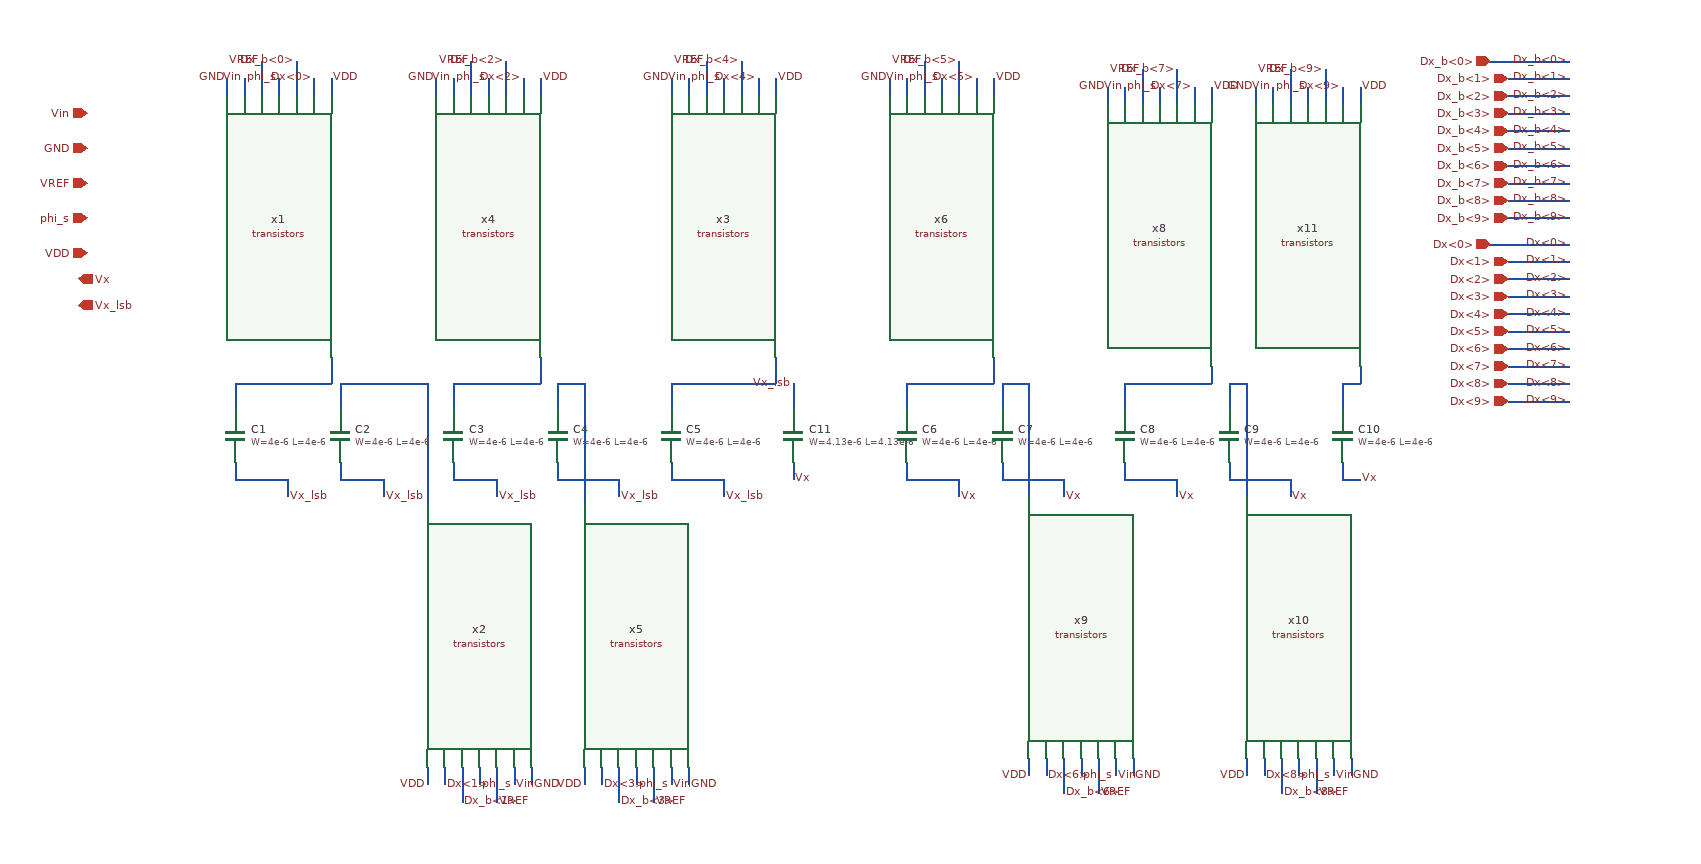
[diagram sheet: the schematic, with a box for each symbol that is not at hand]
v {xschem version=3.4.8RC file_version=1.3}
G {}
K {}
V {}
S {}
F {}
E {}
N -220 -110 -220 -90 {lab=Vx_lsb}
N -100 -110 -100 -90 {lab=Vx_lsb}
N 30 -110 30 -90 {lab=Vx_lsb}
N 150 -110 150 -90 {lab=Vx_lsb}
N 280 -110 280 -90 {lab=Vx_lsb}
N 920 -110 920 -90 {lab=Vx}
N 800 -110 800 -90 {lab=Vx}
N 660 -110 660 -90 {lab=Vx}
N 550 -110 550 -90 {lab=Vx}
N 420 -110 420 -90 {lab=Vx}
N -100 -200 -100 -170 {lab=#net1}
N -220 -200 -220 -170 {lab=#net2}
N 30 -200 30 -170 {lab=#net3}
N 150 -200 150 -170 {lab=#net4}
N 280 -200 280 -170 {lab=#net5}
N 550 -200 550 -170 {lab=#net6}
N 660 -200 660 -170 {lab=#net7}
N 800 -200 800 -170 {lab=#net8}
N 920 -200 920 -170 {lab=#net9}
N 1050 -110 1050 -90 {lab=Vx}
N -110 -230 -110 -200 {lab=#net2}
N -0 -200 0 -60 {lab=#net1}
N 180 -200 180 -70 {lab=#net4}
N 180 -70 180 -60 {lab=#net4}
N 130 -230 130 -200 {lab=#net3}
N 400 -230 400 -200 {lab=#net5}
N 650 -230 650 -200 {lab=#net6}
N 940 -200 940 -70 {lab=#net9}
N 900 -220 900 -200 {lab=#net8}
N 690 -200 690 -70 {lab=#net7}
N -230 -550 -230 -530 {lab=GND}
N -210 -550 -210 -530 {lab=Vin}
N -190 -550 -190 -530 {lab=VREF}
N -170 -550 -170 -530 {lab=phi_s}
N -150 -550 -150 -530 {lab=Dx_b<0>}
N -130 -550 -130 -530 {lab=Dx<0>}
N -110 -550 -110 -530 {lab=VDD}
N -190 -570 -190 -550 {lab=VREF}
N -150 -570 -150 -550 {lab=Dx_b<0>}
N 10 -550 10 -530 {lab=GND}
N 30 -550 30 -530 {lab=Vin}
N 50 -550 50 -530 {lab=VREF}
N 70 -550 70 -530 {lab=phi_s}
N 90 -550 90 -530 {lab=Dx_b<2>}
N 110 -550 110 -530 {lab=Dx<2>}
N 130 -550 130 -530 {lab=VDD}
N 50 -570 50 -550 {lab=VREF}
N 90 -570 90 -550 {lab=Dx_b<2>}
N 280 -550 280 -530 {lab=GND}
N 300 -550 300 -530 {lab=Vin}
N 320 -550 320 -530 {lab=VREF}
N 340 -550 340 -530 {lab=phi_s}
N 360 -550 360 -530 {lab=Dx_b<4>}
N 380 -550 380 -530 {lab=Dx<4>}
N 400 -550 400 -530 {lab=VDD}
N 320 -570 320 -550 {lab=VREF}
N 360 -570 360 -550 {lab=Dx_b<4>}
N 530 -550 530 -530 {lab=GND}
N 550 -550 550 -530 {lab=Vin}
N 570 -550 570 -530 {lab=VREF}
N 590 -550 590 -530 {lab=phi_s}
N 610 -550 610 -530 {lab=Dx_b<5>}
N 630 -550 630 -530 {lab=Dx<5>}
N 650 -550 650 -530 {lab=VDD}
N 570 -570 570 -550 {lab=VREF}
N 610 -570 610 -550 {lab=Dx_b<5>}
N 780 -540 780 -520 {lab=GND}
N 800 -540 800 -520 {lab=Vin}
N 820 -540 820 -520 {lab=VREF}
N 840 -540 840 -520 {lab=phi_s}
N 860 -540 860 -520 {lab=Dx_b<7>}
N 880 -540 880 -520 {lab=Dx<7>}
N 900 -540 900 -520 {lab=VDD}
N 820 -560 820 -540 {lab=VREF}
N 860 -560 860 -540 {lab=Dx_b<7>}
N 120 240 120 260 {lab=GND}
N 100 240 100 260 {lab=Vin}
N 80 240 80 260 {lab=VREF}
N 60 240 60 260 {lab=phi_s}
N 40 240 40 260 {lab=Dx_b<1>}
N 20 240 20 260 {lab=Dx<1>}
N 0 240 0 260 {lab=VDD}
N 80 260 80 280 {lab=VREF}
N 40 260 40 280 {lab=Dx_b<1>}
N 300 240 300 260 {lab=GND}
N 280 240 280 260 {lab=Vin}
N 260 240 260 260 {lab=VREF}
N 240 240 240 260 {lab=phi_s}
N 220 240 220 260 {lab=Dx_b<3>}
N 200 240 200 260 {lab=Dx<3>}
N 180 240 180 260 {lab=VDD}
N 260 260 260 280 {lab=VREF}
N 220 260 220 280 {lab=Dx_b<3>}
N 810 230 810 250 {lab=GND}
N 790 230 790 250 {lab=Vin}
N 770 230 770 250 {lab=VREF}
N 750 230 750 250 {lab=phi_s}
N 730 230 730 250 {lab=Dx_b<6>}
N 710 230 710 250 {lab=Dx<6>}
N 690 230 690 250 {lab=VDD}
N 770 250 770 270 {lab=VREF}
N 730 250 730 270 {lab=Dx_b<6>}
N 1060 230 1060 250 {lab=GND}
N 1040 230 1040 250 {lab=Vin}
N 1020 230 1020 250 {lab=VREF}
N 1000 230 1000 250 {lab=phi_s}
N 980 230 980 250 {lab=Dx_b<8>}
N 960 230 960 250 {lab=Dx<8>}
N 940 230 940 250 {lab=VDD}
N 1020 250 1020 270 {lab=VREF}
N 980 250 980 270 {lab=Dx_b<8>}
N 990 -90 990 -70 {lab=Vx}
N 860 -90 860 -70 {lab=Vx}
N 730 -90 730 -80 {lab=Vx}
N 1050 -90 1070 -90 {lab=Vx}
N 730 -80 730 -70 {lab=Vx}
N 610 -90 610 -70 {lab=Vx}
N 340 -90 340 -70 {lab=Vx_lsb}
N 220 -90 220 -70 {lab=Vx_lsb}
N -50 -90 -50 -70 {lab=Vx_lsb}
N 80 -90 80 -70 {lab=Vx_lsb}
N -160 -90 -160 -70 {lab=Vx_lsb}
N -220 -90 -160 -90 {lab=Vx_lsb}
N -100 -90 -50 -90 {lab=Vx_lsb}
N 30 -90 80 -90 {lab=Vx_lsb}
N 150 -90 220 -90 {lab=Vx_lsb}
N 280 -90 340 -90 {lab=Vx_lsb}
N 920 -90 990 -90 {lab=Vx}
N 800 -90 860 -90 {lab=Vx}
N 660 -90 730 -90 {lab=Vx}
N 550 -90 610 -90 {lab=Vx}
N 1220 -570 1310 -570 {lab=Dx_b<0>}
N 1240 -550 1310 -550 {lab=Dx_b<1>}
N 1240 -530 1310 -530 {lab=Dx_b<2>}
N 1240 -510 1310 -510 {lab=Dx_b<3>}
N 1240 -490 1310 -490 {lab=Dx_b<4>}
N 1240 -470 1310 -470 {lab=Dx_b<5>}
N 1240 -450 1310 -450 {lab=Dx_b<6>}
N 1240 -430 1310 -430 {lab=Dx_b<7>}
N 1240 -410 1310 -410 {lab=Dx_b<8>}
N 1240 -390 1310 -390 {lab=Dx_b<9>}
N 1220 -360 1310 -360 {lab=Dx<0>}
N 1240 -340 1310 -340 {lab=Dx<1>}
N 1240 -320 1310 -320 {lab=Dx<2>}
N 1240 -300 1310 -300 {lab=Dx<3>}
N 1240 -280 1310 -280 {lab=Dx<4>}
N 1240 -260 1310 -260 {lab=Dx<5>}
N 1240 -240 1310 -240 {lab=Dx<6>}
N 1240 -220 1310 -220 {lab=Dx<7>}
N 1240 -200 1310 -200 {lab=Dx<8>}
N 1240 -180 1310 -180 {lab=Dx<9>}
N -100 -200 0 -200 {lab=#net1}
N -220 -200 -110 -200 {lab=#net2}
N 30 -200 130 -200 {lab=#net3}
N 150 -200 180 -200 {lab=#net4}
N 280 -200 400 -200 {lab=#net5}
N 550 -200 650 -200 {lab=#net6}
N 660 -200 690 -200 {lab=#net7}
N 800 -200 900 -200 {lab=#net8}
N 920 -200 940 -200 {lab=#net9}
N 1070 -220 1070 -200 {lab=#net10}
N 1050 -200 1070 -200 {lab=#net10}
N 1050 -200 1050 -170 {lab=#net10}
N 950 -540 950 -520 {lab=GND}
N 970 -540 970 -520 {lab=Vin}
N 990 -540 990 -520 {lab=VREF}
N 1010 -540 1010 -520 {lab=phi_s}
N 1030 -540 1030 -520 {lab=Dx_b<9>}
N 1050 -540 1050 -520 {lab=Dx<9>}
N 1070 -540 1070 -520 {lab=VDD}
N 990 -560 990 -540 {lab=VREF}
N 1030 -560 1030 -540 {lab=Dx_b<9>}
N 420 -200 420 -170 {lab=Vx_lsb}
C {symbols/cap_mim_2f0fF.sym} -220 -140 0 0 {name=C1
W=4e-6
L=4e-6
model=cap_mim_2f0fF
spiceprefix=X
m=1}
C {symbols/cap_mim_2f0fF.sym} -100 -140 0 0 {name=C2
W=4e-6
L=4e-6
model=cap_mim_2f0fF
spiceprefix=X
m=1}
C {symbols/cap_mim_2f0fF.sym} 30 -140 0 0 {name=C3
W=4e-6
L=4e-6
model=cap_mim_2f0fF
spiceprefix=X
m=2}
C {symbols/cap_mim_2f0fF.sym} 150 -140 0 0 {name=C4
W=4e-6
L=4e-6
model=cap_mim_2f0fF
spiceprefix=X
m=4}
C {symbols/cap_mim_2f0fF.sym} 280 -140 0 0 {name=C5
W=4e-6
L=4e-6
model=cap_mim_2f0fF
spiceprefix=X
m=8}
C {symbols/cap_mim_2f0fF.sym} 550 -140 0 0 {name=C6
W=4e-6
L=4e-6
model=cap_mim_2f0fF
spiceprefix=X
m=1}
C {symbols/cap_mim_2f0fF.sym} 660 -140 0 0 {name=C7
W=4e-6
L=4e-6
model=cap_mim_2f0fF
spiceprefix=X
m=1}
C {symbols/cap_mim_2f0fF.sym} 800 -140 0 0 {name=C8
W=4e-6
L=4e-6
model=cap_mim_2f0fF
spiceprefix=X
m=2}
C {symbols/cap_mim_2f0fF.sym} 920 -140 0 0 {name=C9
W=4e-6
L=4e-6
model=cap_mim_2f0fF
spiceprefix=X
m=4}
C {symbols/cap_mim_2f0fF.sym} 1050 -140 0 0 {name=C10
W=4e-6
L=4e-6
model=cap_mim_2f0fF
spiceprefix=X
m=8}
C {symbols/cap_mim_2f0fF.sym} 420 -140 0 0 {name=C11
W=4.13e-6
L=4.13e-6
model=cap_mim_2f0fF
spiceprefix=X
m=1}
C {lab_wire.sym} 990 -70 2 0 {name=p10 sig_type=std_logic lab=Vx}
C {cdac/transistors.sym} -170 -380 1 0 {name=x1}
C {cdac/transistors.sym} 60 90 3 0 {name=x2}
C {cdac/transistors.sym} 340 -380 1 0 {name=x3}
C {cdac/transistors.sym} 70 -380 1 0 {name=x4}
C {cdac/transistors.sym} 240 90 3 0 {name=x5}
C {cdac/transistors.sym} 590 -380 1 0 {name=x6}
C {cdac/transistors.sym} 840 -370 1 0 {name=x8}
C {cdac/transistors.sym} 750 80 3 0 {name=x9}
C {cdac/transistors.sym} 1000 80 3 0 {name=x10}
C {ipin.sym} -390 -510 0 0 {name=p1 lab=Vin}
C {ipin.sym} -390 -470 0 0 {name=p2 lab=GND}
C {ipin.sym} -390 -430 0 0 {name=p3 lab=VREF}
C {opin.sym} -400 -320 0 0 {name=p4 lab=Vx}
C {ipin.sym} -390 -390 0 0 {name=p5 lab=phi_s}
C {ipin.sym} -390 -350 0 0 {name=p6 lab=VDD}
C {ipin.sym} 1220 -570 0 0 {name=p7 lab=Dx_b<0>}
C {ipin.sym} 1220 -360 0 0 {name=p8 lab=Dx<0>}
C {lab_wire.sym} -230 -550 0 0 {name=p9 sig_type=std_logic lab=GND}
C {lab_wire.sym} -210 -550 0 0 {name=p11 sig_type=std_logic lab=Vin}
C {lab_wire.sym} -110 -550 2 0 {name=p12 sig_type=std_logic lab=VDD}
C {lab_wire.sym} -190 -570 0 0 {name=p13 sig_type=std_logic lab=VREF}
C {lab_wire.sym} -170 -550 0 0 {name=p14 sig_type=std_logic lab=phi_s}
C {lab_wire.sym} -150 -570 0 0 {name=p15 sig_type=std_logic lab=Dx_b<0>}
C {lab_wire.sym} -130 -550 0 0 {name=p16 sig_type=std_logic lab=Dx<0>}
C {lab_wire.sym} 10 -550 0 0 {name=p17 sig_type=std_logic lab=GND}
C {lab_wire.sym} 30 -550 0 0 {name=p18 sig_type=std_logic lab=Vin}
C {lab_wire.sym} 130 -550 2 0 {name=p19 sig_type=std_logic lab=VDD}
C {lab_wire.sym} 50 -570 0 0 {name=p20 sig_type=std_logic lab=VREF}
C {lab_wire.sym} 70 -550 0 0 {name=p21 sig_type=std_logic lab=phi_s}
C {lab_wire.sym} 90 -570 0 0 {name=p22 sig_type=std_logic lab=Dx_b<2>}
C {lab_wire.sym} 110 -550 0 0 {name=p23 sig_type=std_logic lab=Dx<2>}
C {lab_wire.sym} 280 -550 0 0 {name=p24 sig_type=std_logic lab=GND}
C {lab_wire.sym} 300 -550 0 0 {name=p25 sig_type=std_logic lab=Vin}
C {lab_wire.sym} 400 -550 2 0 {name=p26 sig_type=std_logic lab=VDD}
C {lab_wire.sym} 320 -570 0 0 {name=p27 sig_type=std_logic lab=VREF}
C {lab_wire.sym} 340 -550 0 0 {name=p28 sig_type=std_logic lab=phi_s}
C {lab_wire.sym} 360 -570 0 0 {name=p29 sig_type=std_logic lab=Dx_b<4>}
C {lab_wire.sym} 380 -550 0 0 {name=p30 sig_type=std_logic lab=Dx<4>}
C {lab_wire.sym} 530 -550 0 0 {name=p31 sig_type=std_logic lab=GND}
C {lab_wire.sym} 550 -550 0 0 {name=p32 sig_type=std_logic lab=Vin}
C {lab_wire.sym} 650 -550 2 0 {name=p33 sig_type=std_logic lab=VDD}
C {lab_wire.sym} 570 -570 0 0 {name=p34 sig_type=std_logic lab=VREF}
C {lab_wire.sym} 590 -550 0 0 {name=p35 sig_type=std_logic lab=phi_s}
C {lab_wire.sym} 610 -570 0 0 {name=p36 sig_type=std_logic lab=Dx_b<5>}
C {lab_wire.sym} 630 -550 0 0 {name=p37 sig_type=std_logic lab=Dx<5>}
C {lab_wire.sym} 780 -540 0 0 {name=p38 sig_type=std_logic lab=GND}
C {lab_wire.sym} 800 -540 0 0 {name=p39 sig_type=std_logic lab=Vin}
C {lab_wire.sym} 900 -540 2 0 {name=p40 sig_type=std_logic lab=VDD}
C {lab_wire.sym} 820 -560 0 0 {name=p41 sig_type=std_logic lab=VREF}
C {lab_wire.sym} 840 -540 0 0 {name=p42 sig_type=std_logic lab=phi_s}
C {lab_wire.sym} 860 -560 0 0 {name=p43 sig_type=std_logic lab=Dx_b<7>}
C {lab_wire.sym} 880 -540 0 0 {name=p44 sig_type=std_logic lab=Dx<7>}
C {lab_wire.sym} 120 260 2 0 {name=p45 sig_type=std_logic lab=GND}
C {lab_wire.sym} 100 260 2 0 {name=p46 sig_type=std_logic lab=Vin}
C {lab_wire.sym} 0 260 0 0 {name=p47 sig_type=std_logic lab=VDD}
C {lab_wire.sym} 80 280 2 0 {name=p48 sig_type=std_logic lab=VREF}
C {lab_wire.sym} 60 260 2 0 {name=p49 sig_type=std_logic lab=phi_s}
C {lab_wire.sym} 40 280 2 0 {name=p50 sig_type=std_logic lab=Dx_b<1>}
C {lab_wire.sym} 20 260 2 0 {name=p51 sig_type=std_logic lab=Dx<1>}
C {lab_wire.sym} 300 260 2 0 {name=p52 sig_type=std_logic lab=GND}
C {lab_wire.sym} 280 260 2 0 {name=p53 sig_type=std_logic lab=Vin}
C {lab_wire.sym} 180 260 0 0 {name=p54 sig_type=std_logic lab=VDD}
C {lab_wire.sym} 260 280 2 0 {name=p55 sig_type=std_logic lab=VREF}
C {lab_wire.sym} 240 260 2 0 {name=p56 sig_type=std_logic lab=phi_s}
C {lab_wire.sym} 220 280 2 0 {name=p57 sig_type=std_logic lab=Dx_b<3>}
C {lab_wire.sym} 200 260 2 0 {name=p58 sig_type=std_logic lab=Dx<3>}
C {lab_wire.sym} 810 250 2 0 {name=p66 sig_type=std_logic lab=GND}
C {lab_wire.sym} 790 250 2 0 {name=p67 sig_type=std_logic lab=Vin}
C {lab_wire.sym} 690 250 0 0 {name=p68 sig_type=std_logic lab=VDD}
C {lab_wire.sym} 770 270 2 0 {name=p69 sig_type=std_logic lab=VREF}
C {lab_wire.sym} 750 250 2 0 {name=p70 sig_type=std_logic lab=phi_s}
C {lab_wire.sym} 730 270 2 0 {name=p71 sig_type=std_logic lab=Dx_b<6>}
C {lab_wire.sym} 710 250 2 0 {name=p72 sig_type=std_logic lab=Dx<6>}
C {lab_wire.sym} 1060 250 2 0 {name=p73 sig_type=std_logic lab=GND}
C {lab_wire.sym} 1040 250 2 0 {name=p74 sig_type=std_logic lab=Vin}
C {lab_wire.sym} 940 250 0 0 {name=p75 sig_type=std_logic lab=VDD}
C {lab_wire.sym} 1020 270 2 0 {name=p76 sig_type=std_logic lab=VREF}
C {lab_wire.sym} 1000 250 2 0 {name=p77 sig_type=std_logic lab=phi_s}
C {lab_wire.sym} 980 270 2 0 {name=p78 sig_type=std_logic lab=Dx_b<8>}
C {lab_wire.sym} 960 250 2 0 {name=p79 sig_type=std_logic lab=Dx<8>}
C {lab_wire.sym} 860 -70 2 0 {name=p80 sig_type=std_logic lab=Vx}
C {lab_wire.sym} 730 -70 2 0 {name=p81 sig_type=std_logic lab=Vx}
C {lab_wire.sym} 1070 -90 2 0 {name=p82 sig_type=std_logic lab=Vx}
C {lab_wire.sym} 610 -70 2 0 {name=p83 sig_type=std_logic lab=Vx}
C {lab_wire.sym} 420 -90 2 0 {name=p84 sig_type=std_logic lab=Vx}
C {lab_wire.sym} 340 -70 2 0 {name=p85 sig_type=std_logic lab=Vx_lsb}
C {lab_wire.sym} 220 -70 2 0 {name=p86 sig_type=std_logic lab=Vx_lsb}
C {lab_wire.sym} 80 -70 2 0 {name=p87 sig_type=std_logic lab=Vx_lsb}
C {lab_wire.sym} -50 -70 2 0 {name=p88 sig_type=std_logic lab=Vx_lsb}
C {lab_wire.sym} -160 -70 2 0 {name=p89 sig_type=std_logic lab=Vx_lsb}
C {lab_wire.sym} 1310 -570 0 0 {name=p90 sig_type=std_logic lab=Dx_b<0>}
C {lab_wire.sym} 1310 -550 0 0 {name=p91 sig_type=std_logic lab=Dx_b<1>}
C {lab_wire.sym} 1310 -530 0 0 {name=p92 sig_type=std_logic lab=Dx_b<2>}
C {lab_wire.sym} 1310 -510 0 0 {name=p93 sig_type=std_logic lab=Dx_b<3>}
C {lab_wire.sym} 1310 -490 0 0 {name=p94 sig_type=std_logic lab=Dx_b<4>}
C {lab_wire.sym} 1310 -470 0 0 {name=p95 sig_type=std_logic lab=Dx_b<5>}
C {lab_wire.sym} 1310 -450 0 0 {name=p96 sig_type=std_logic lab=Dx_b<6>}
C {lab_wire.sym} 1310 -430 0 0 {name=p97 sig_type=std_logic lab=Dx_b<7>}
C {lab_wire.sym} 1310 -410 0 0 {name=p98 sig_type=std_logic lab=Dx_b<8>}
C {lab_wire.sym} 1310 -390 0 0 {name=p99 sig_type=std_logic lab=Dx_b<9>}
C {lab_wire.sym} 1310 -360 0 0 {name=p100 sig_type=std_logic lab=Dx<0>}
C {lab_wire.sym} 1310 -340 0 0 {name=p101 sig_type=std_logic lab=Dx<1>}
C {lab_wire.sym} 1310 -320 0 0 {name=p102 sig_type=std_logic lab=Dx<2>}
C {lab_wire.sym} 1310 -300 0 0 {name=p103 sig_type=std_logic lab=Dx<3>}
C {lab_wire.sym} 1310 -280 0 0 {name=p104 sig_type=std_logic lab=Dx<4>}
C {lab_wire.sym} 1310 -260 0 0 {name=p105 sig_type=std_logic lab=Dx<5>}
C {lab_wire.sym} 1310 -240 0 0 {name=p106 sig_type=std_logic lab=Dx<6>}
C {lab_wire.sym} 1310 -220 0 0 {name=p107 sig_type=std_logic lab=Dx<7>}
C {lab_wire.sym} 1310 -200 0 0 {name=p108 sig_type=std_logic lab=Dx<8>}
C {lab_wire.sym} 1310 -180 0 0 {name=p109 sig_type=std_logic lab=Dx<9>}
C {ipin.sym} 1240 -550 0 0 {name=p110 lab=Dx_b<1>}
C {ipin.sym} 1240 -530 0 0 {name=p111 lab=Dx_b<2>}
C {ipin.sym} 1240 -510 0 0 {name=p112 lab=Dx_b<3>}
C {ipin.sym} 1240 -490 0 0 {name=p113 lab=Dx_b<4>}
C {ipin.sym} 1240 -470 0 0 {name=p114 lab=Dx_b<5>}
C {ipin.sym} 1240 -450 0 0 {name=p115 lab=Dx_b<6>}
C {ipin.sym} 1240 -430 0 0 {name=p116 lab=Dx_b<7>}
C {ipin.sym} 1240 -410 0 0 {name=p117 lab=Dx_b<8>}
C {ipin.sym} 1240 -390 0 0 {name=p118 lab=Dx_b<9>}
C {ipin.sym} 1240 -340 0 0 {name=p119 lab=Dx<1>}
C {ipin.sym} 1240 -320 0 0 {name=p120 lab=Dx<2>}
C {ipin.sym} 1240 -300 0 0 {name=p121 lab=Dx<3>}
C {ipin.sym} 1240 -280 0 0 {name=p122 lab=Dx<4>}
C {ipin.sym} 1240 -260 0 0 {name=p123 lab=Dx<5>}
C {ipin.sym} 1240 -240 0 0 {name=p124 lab=Dx<6>}
C {ipin.sym} 1240 -220 0 0 {name=p125 lab=Dx<7>}
C {ipin.sym} 1240 -200 0 0 {name=p126 lab=Dx<8>}
C {ipin.sym} 1240 -180 0 0 {name=p127 lab=Dx<9>}
C {cdac/transistors.sym} 1010 -370 1 0 {name=x11}
C {lab_wire.sym} 950 -540 0 0 {name=p128 sig_type=std_logic lab=GND}
C {lab_wire.sym} 970 -540 0 0 {name=p129 sig_type=std_logic lab=Vin}
C {lab_wire.sym} 1070 -540 2 0 {name=p130 sig_type=std_logic lab=VDD}
C {lab_wire.sym} 990 -560 0 0 {name=p131 sig_type=std_logic lab=VREF}
C {lab_wire.sym} 1010 -540 0 0 {name=p132 sig_type=std_logic lab=phi_s}
C {lab_wire.sym} 1030 -560 0 0 {name=p133 sig_type=std_logic lab=Dx_b<9>}
C {lab_wire.sym} 1050 -540 0 0 {name=p134 sig_type=std_logic lab=Dx<9>}
C {lab_wire.sym} 420 -200 0 0 {name=p59 sig_type=std_logic lab=Vx_lsb}
C {opin.sym} -400 -290 0 0 {name=p60 lab=Vx_lsb}
